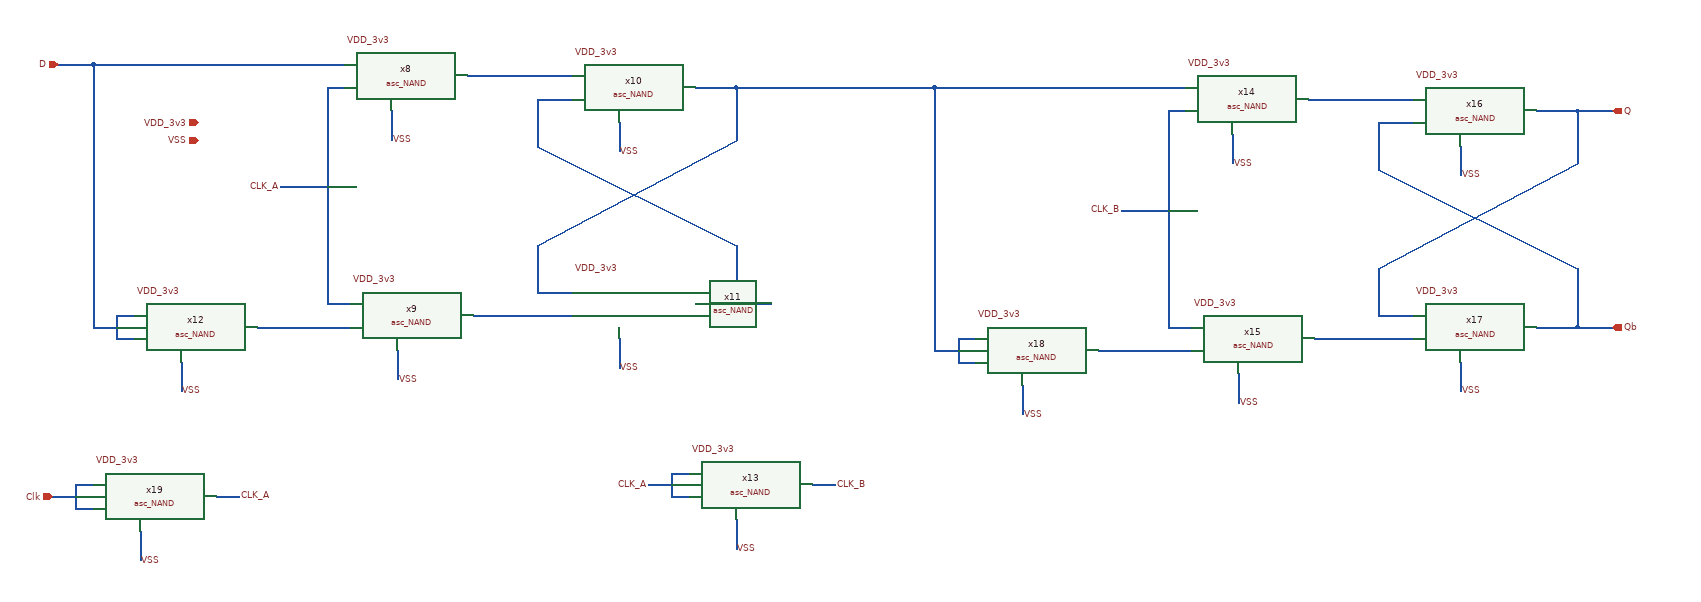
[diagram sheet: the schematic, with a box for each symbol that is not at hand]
v {xschem version=3.4.8RC file_version=1.3}
G {}
K {}
V {}
S {}
F {}
E {}
N 580 -890 610 -890 {lab=CLK_A}
N 580 -890 580 -520 {lab=CLK_A}
N 580 -520 620 -520 {lab=CLK_A}
N 460 -480 620 -480 {lab=#net1}
N 830 -500 1000 -500 {lab=#net2}
N 820 -910 1000 -910 {lab=#net3}
N 940 -540 1000 -540 {lab=#net4}
N 940 -620 940 -540 {lab=#net4}
N 940 -620 1280 -800 {lab=#net4}
N 1280 -890 1280 -800 {lab=#net4}
N 1210 -890 1280 -890 {lab=#net4}
N 940 -870 1000 -870 {lab=#net5}
N 940 -870 940 -790 {lab=#net5}
N 940 -790 1280 -620 {lab=#net5}
N 1280 -620 1280 -520 {lab=#net5}
N 1210 -520 1280 -520 {lab=#net5}
N 1280 -520 1340 -520 {lab=#net5}
N 1280 -890 1340 -890 {lab=#net4}
N 220 -500 250 -500 {lab=D}
N 220 -500 220 -460 {lab=D}
N 220 -460 250 -460 {lab=D}
N 180 -480 220 -480 {lab=D}
N 180 -930 610 -930 {lab=D}
N 180 -930 180 -480 {lab=D}
N 120 -930 180 -930 {lab=D}
N 500 -720 580 -720 {lab=CLK_A}
N 1170 -230 1200 -230 {lab=CLK_A}
N 1170 -230 1170 -190 {lab=CLK_A}
N 1170 -190 1200 -190 {lab=CLK_A}
N 1130 -210 1170 -210 {lab=CLK_A}
N 1410 -210 1450 -210 {lab=CLK_B}
N 2020 -850 2050 -850 {lab=CLK_B}
N 2020 -850 2020 -480 {lab=CLK_B}
N 2020 -480 2060 -480 {lab=CLK_B}
N 1900 -440 2060 -440 {lab=#net6}
N 2270 -460 2440 -460 {lab=#net7}
N 2260 -870 2440 -870 {lab=#net8}
N 2380 -500 2440 -500 {lab=Q}
N 2380 -580 2380 -500 {lab=Q}
N 2380 -580 2720 -760 {lab=Q}
N 2720 -850 2720 -760 {lab=Q}
N 2650 -850 2720 -850 {lab=Q}
N 2380 -830 2440 -830 {lab=Qb}
N 2380 -830 2380 -750 {lab=Qb}
N 2380 -750 2720 -580 {lab=Qb}
N 2720 -580 2720 -480 {lab=Qb}
N 2650 -480 2720 -480 {lab=Qb}
N 2720 -480 2780 -480 {lab=Qb}
N 2720 -850 2780 -850 {lab=Q}
N 1660 -460 1690 -460 {lab=#net4}
N 1660 -460 1660 -420 {lab=#net4}
N 1660 -420 1690 -420 {lab=#net4}
N 1620 -440 1660 -440 {lab=#net4}
N 1620 -890 2050 -890 {lab=#net4}
N 1620 -890 1620 -440 {lab=#net4}
N 1560 -890 1620 -890 {lab=#net4}
N 1940 -680 2020 -680 {lab=CLK_B}
N 1340 -890 1560 -890 {lab=#net4}
N 150 -210 180 -210 {lab=Clk}
N 150 -210 150 -170 {lab=Clk}
N 150 -170 180 -170 {lab=Clk}
N 110 -190 150 -190 {lab=Clk}
N 390 -190 430 -190 {lab=CLK_A}
N 690 -850 690 -800 {lab=VSS}
N 330 -420 330 -370 {lab=VSS}
N 260 -130 260 -80 {lab=VSS}
N 700 -440 700 -390 {lab=VSS}
N 1080 -460 1080 -410 {lab=VSS}
N 1080 -830 1080 -780 {lab=VSS}
N 1280 -150 1280 -100 {lab=VSS}
N 1770 -380 1770 -330 {lab=VSS}
N 2140 -400 2140 -350 {lab=VSS}
N 2130 -810 2130 -760 {lab=VSS}
N 2520 -790 2520 -740 {lab=VSS}
N 2520 -420 2520 -370 {lab=VSS}
C {Analog/schematics/1_readout/slopedetector/nand/asc_NAND.sym} 690 -910 0 0 {name=x8}
C {Analog/schematics/1_readout/slopedetector/nand/asc_NAND.sym} 700 -500 0 0 {name=x9}
C {Analog/schematics/1_readout/slopedetector/nand/asc_NAND.sym} 1080 -890 0 0 {name=x10}
C {Analog/schematics/1_readout/slopedetector/nand/asc_NAND.sym} 1080 -520 0 0 {name=x11}
C {Analog/schematics/1_readout/slopedetector/nand/asc_NAND.sym} 330 -480 0 0 {name=x12}
C {lab_pin.sym} 1130 -210 0 0 {name=p39 sig_type=std_logic lab=CLK_A}
C {Analog/schematics/1_readout/slopedetector/nand/asc_NAND.sym} 1280 -210 0 0 {name=x13}
C {lab_pin.sym} 1450 -210 0 1 {name=p41 sig_type=std_logic lab=CLK_B}
C {Analog/schematics/1_readout/slopedetector/nand/asc_NAND.sym} 2130 -870 0 0 {name=x14}
C {Analog/schematics/1_readout/slopedetector/nand/asc_NAND.sym} 2140 -460 0 0 {name=x15}
C {Analog/schematics/1_readout/slopedetector/nand/asc_NAND.sym} 2520 -850 0 0 {name=x16}
C {Analog/schematics/1_readout/slopedetector/nand/asc_NAND.sym} 2520 -480 0 0 {name=x17}
C {Analog/schematics/1_readout/slopedetector/nand/asc_NAND.sym} 1770 -440 0 0 {name=x18}
C {lab_pin.sym} 1940 -680 0 0 {name=p37 sig_type=std_logic lab=CLK_B}
C {Analog/schematics/1_readout/slopedetector/nand/asc_NAND.sym} 260 -190 0 0 {name=x19}
C {lab_pin.sym} 430 -190 0 1 {name=p48 sig_type=std_logic lab=CLK_A}
C {lab_pin.sym} 500 -720 0 0 {name=p35 sig_type=std_logic lab=CLK_A}
C {iopin.sym} 360 -830 2 0 {name=p11 lab=VDD_3v3}
C {iopin.sym} 360 -800 2 0 {name=p12 lab=VSS}
C {iopin.sym} 2780 -850 2 1 {name=p13 lab=Q}
C {iopin.sym} 2780 -480 2 1 {name=p14 lab=Qb}
C {iopin.sym} 120 -930 2 0 {name=p15 lab=D}
C {iopin.sym} 110 -190 2 0 {name=p16 lab=Clk}
C {lab_pin.sym} 690 -970 3 1 {name=p1 sig_type=std_logic lab=VDD_3v3}
C {lab_pin.sym} 690 -800 0 1 {name=p2 sig_type=std_logic lab=VSS}
C {lab_pin.sym} 330 -540 3 1 {name=p3 sig_type=std_logic lab=VDD_3v3}
C {lab_pin.sym} 330 -370 0 1 {name=p4 sig_type=std_logic lab=VSS}
C {lab_pin.sym} 260 -250 3 1 {name=p5 sig_type=std_logic lab=VDD_3v3}
C {lab_pin.sym} 260 -80 0 1 {name=p6 sig_type=std_logic lab=VSS}
C {lab_pin.sym} 700 -560 3 1 {name=p7 sig_type=std_logic lab=VDD_3v3}
C {lab_pin.sym} 700 -390 0 1 {name=p8 sig_type=std_logic lab=VSS}
C {lab_pin.sym} 1080 -580 3 1 {name=p9 sig_type=std_logic lab=VDD_3v3}
C {lab_pin.sym} 1080 -410 0 1 {name=p10 sig_type=std_logic lab=VSS}
C {lab_pin.sym} 1080 -950 3 1 {name=p17 sig_type=std_logic lab=VDD_3v3}
C {lab_pin.sym} 1080 -780 0 1 {name=p18 sig_type=std_logic lab=VSS}
C {lab_pin.sym} 1280 -270 3 1 {name=p19 sig_type=std_logic lab=VDD_3v3}
C {lab_pin.sym} 1280 -100 0 1 {name=p20 sig_type=std_logic lab=VSS}
C {lab_pin.sym} 1770 -500 3 1 {name=p21 sig_type=std_logic lab=VDD_3v3}
C {lab_pin.sym} 1770 -330 0 1 {name=p22 sig_type=std_logic lab=VSS}
C {lab_pin.sym} 2140 -520 3 1 {name=p23 sig_type=std_logic lab=VDD_3v3}
C {lab_pin.sym} 2140 -350 0 1 {name=p24 sig_type=std_logic lab=VSS}
C {lab_pin.sym} 2130 -930 3 1 {name=p25 sig_type=std_logic lab=VDD_3v3}
C {lab_pin.sym} 2130 -760 0 1 {name=p26 sig_type=std_logic lab=VSS}
C {lab_pin.sym} 2520 -910 3 1 {name=p27 sig_type=std_logic lab=VDD_3v3}
C {lab_pin.sym} 2520 -740 0 1 {name=p28 sig_type=std_logic lab=VSS}
C {lab_pin.sym} 2520 -540 3 1 {name=p29 sig_type=std_logic lab=VDD_3v3}
C {lab_pin.sym} 2520 -370 0 1 {name=p30 sig_type=std_logic lab=VSS}
